VERSION 5.7 ;
  NOWIREEXTENSIONATPIN ON ;
  DIVIDERCHAR "/" ;
  BUSBITCHARS "[]" ;
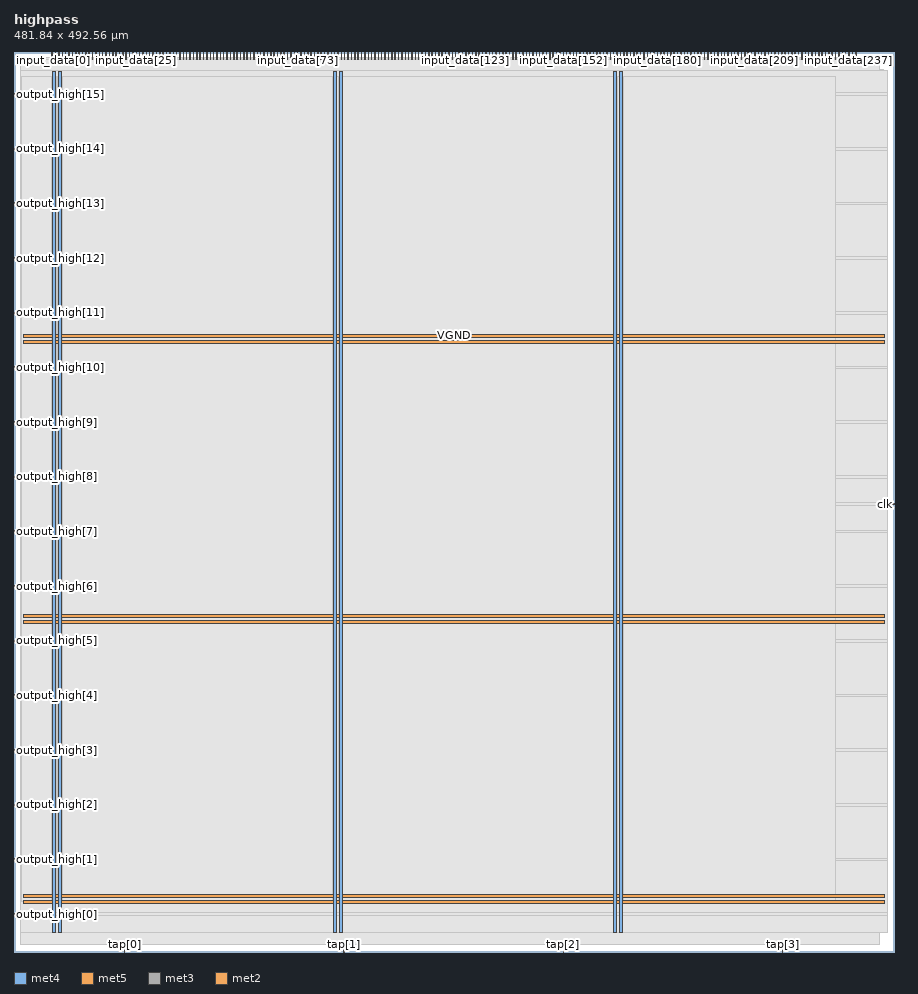
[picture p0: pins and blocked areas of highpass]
MACRO highpass
  CLASS BLOCK ;
  FOREIGN highpass ;
  ORIGIN 0.000 0.000 ;
  SIZE 481.840 BY 492.560 ;
  PIN VGND
    DIRECTION INOUT ;
    USE GROUND ;
    PORT
      LAYER met4 ;
        RECT 24.340 10.640 25.940 481.680 ;
    END
    PORT
      LAYER met4 ;
        RECT 177.940 10.640 179.540 481.680 ;
    END
    PORT
      LAYER met4 ;
        RECT 331.540 10.640 333.140 481.680 ;
    END
    PORT
      LAYER met5 ;
        RECT 5.280 30.030 476.340 31.630 ;
    END
    PORT
      LAYER met5 ;
        RECT 5.280 183.210 476.340 184.810 ;
    END
    PORT
      LAYER met5 ;
        RECT 5.280 336.390 476.340 337.990 ;
    END
  END VGND
  PIN VPWR
    DIRECTION INOUT ;
    USE POWER ;
    PORT
      LAYER met4 ;
        RECT 21.040 10.640 22.640 481.680 ;
    END
    PORT
      LAYER met4 ;
        RECT 174.640 10.640 176.240 481.680 ;
    END
    PORT
      LAYER met4 ;
        RECT 328.240 10.640 329.840 481.680 ;
    END
    PORT
      LAYER met5 ;
        RECT 5.280 26.730 476.340 28.330 ;
    END
    PORT
      LAYER met5 ;
        RECT 5.280 179.910 476.340 181.510 ;
    END
    PORT
      LAYER met5 ;
        RECT 5.280 333.090 476.340 334.690 ;
    END
  END VPWR
  PIN clk
    DIRECTION INPUT ;
    USE SIGNAL ;
    ANTENNAGATEAREA 0.852000 ;
    ANTENNADIFFAREA 0.434700 ;
    PORT
      LAYER met3 ;
        RECT 477.840 244.840 481.840 245.440 ;
    END
  END clk
  PIN input_data[0]
    DIRECTION INPUT ;
    USE SIGNAL ;
    ANTENNAGATEAREA 0.159000 ;
    PORT
      LAYER met2 ;
        RECT 20.790 488.560 21.070 492.560 ;
    END
  END input_data[0]
  PIN input_data[100]
    DIRECTION INPUT ;
    USE SIGNAL ;
    ANTENNAGATEAREA 0.196500 ;
    PORT
      LAYER met2 ;
        RECT 204.790 488.560 205.070 492.560 ;
    END
  END input_data[100]
  PIN input_data[101]
    DIRECTION INPUT ;
    USE SIGNAL ;
    ANTENNAGATEAREA 0.159000 ;
    PORT
      LAYER met2 ;
        RECT 206.630 488.560 206.910 492.560 ;
    END
  END input_data[101]
  PIN input_data[102]
    DIRECTION INPUT ;
    USE SIGNAL ;
    ANTENNAGATEAREA 0.196500 ;
    PORT
      LAYER met2 ;
        RECT 208.470 488.560 208.750 492.560 ;
    END
  END input_data[102]
  PIN input_data[103]
    DIRECTION INPUT ;
    USE SIGNAL ;
    ANTENNAGATEAREA 0.196500 ;
    PORT
      LAYER met2 ;
        RECT 210.310 488.560 210.590 492.560 ;
    END
  END input_data[103]
  PIN input_data[104]
    DIRECTION INPUT ;
    USE SIGNAL ;
    ANTENNAGATEAREA 0.196500 ;
    PORT
      LAYER met2 ;
        RECT 212.150 488.560 212.430 492.560 ;
    END
  END input_data[104]
  PIN input_data[105]
    DIRECTION INPUT ;
    USE SIGNAL ;
    ANTENNAGATEAREA 0.196500 ;
    PORT
      LAYER met2 ;
        RECT 213.990 488.560 214.270 492.560 ;
    END
  END input_data[105]
  PIN input_data[106]
    DIRECTION INPUT ;
    USE SIGNAL ;
    ANTENNAGATEAREA 0.196500 ;
    PORT
      LAYER met2 ;
        RECT 215.830 488.560 216.110 492.560 ;
    END
  END input_data[106]
  PIN input_data[107]
    DIRECTION INPUT ;
    USE SIGNAL ;
    ANTENNAGATEAREA 0.196500 ;
    PORT
      LAYER met2 ;
        RECT 217.670 488.560 217.950 492.560 ;
    END
  END input_data[107]
  PIN input_data[108]
    DIRECTION INPUT ;
    USE SIGNAL ;
    ANTENNAGATEAREA 0.159000 ;
    PORT
      LAYER met2 ;
        RECT 219.510 488.560 219.790 492.560 ;
    END
  END input_data[108]
  PIN input_data[109]
    DIRECTION INPUT ;
    USE SIGNAL ;
    ANTENNAGATEAREA 0.196500 ;
    PORT
      LAYER met2 ;
        RECT 221.350 488.560 221.630 492.560 ;
    END
  END input_data[109]
  PIN input_data[10]
    DIRECTION INPUT ;
    USE SIGNAL ;
    ANTENNAGATEAREA 0.247500 ;
    PORT
      LAYER met2 ;
        RECT 39.190 488.560 39.470 492.560 ;
    END
  END input_data[10]
  PIN input_data[110]
    DIRECTION INPUT ;
    USE SIGNAL ;
    ANTENNAGATEAREA 0.196500 ;
    PORT
      LAYER met2 ;
        RECT 223.190 488.560 223.470 492.560 ;
    END
  END input_data[110]
  PIN input_data[111]
    DIRECTION INPUT ;
    USE SIGNAL ;
    ANTENNAGATEAREA 0.196500 ;
    PORT
      LAYER met2 ;
        RECT 225.030 488.560 225.310 492.560 ;
    END
  END input_data[111]
  PIN input_data[112]
    DIRECTION INPUT ;
    USE SIGNAL ;
    ANTENNAGATEAREA 0.213000 ;
    PORT
      LAYER met2 ;
        RECT 226.870 488.560 227.150 492.560 ;
    END
  END input_data[112]
  PIN input_data[113]
    DIRECTION INPUT ;
    USE SIGNAL ;
    ANTENNAGATEAREA 0.159000 ;
    PORT
      LAYER met2 ;
        RECT 228.710 488.560 228.990 492.560 ;
    END
  END input_data[113]
  PIN input_data[114]
    DIRECTION INPUT ;
    USE SIGNAL ;
    ANTENNAGATEAREA 0.196500 ;
    PORT
      LAYER met2 ;
        RECT 230.550 488.560 230.830 492.560 ;
    END
  END input_data[114]
  PIN input_data[115]
    DIRECTION INPUT ;
    USE SIGNAL ;
    ANTENNAGATEAREA 0.213000 ;
    PORT
      LAYER met2 ;
        RECT 232.390 488.560 232.670 492.560 ;
    END
  END input_data[115]
  PIN input_data[116]
    DIRECTION INPUT ;
    USE SIGNAL ;
    ANTENNAGATEAREA 0.213000 ;
    PORT
      LAYER met2 ;
        RECT 234.230 488.560 234.510 492.560 ;
    END
  END input_data[116]
  PIN input_data[117]
    DIRECTION INPUT ;
    USE SIGNAL ;
    ANTENNAGATEAREA 0.126000 ;
    PORT
      LAYER met2 ;
        RECT 236.070 488.560 236.350 492.560 ;
    END
  END input_data[117]
  PIN input_data[118]
    DIRECTION INPUT ;
    USE SIGNAL ;
    ANTENNAGATEAREA 0.196500 ;
    PORT
      LAYER met2 ;
        RECT 237.910 488.560 238.190 492.560 ;
    END
  END input_data[118]
  PIN input_data[119]
    DIRECTION INPUT ;
    USE SIGNAL ;
    ANTENNAGATEAREA 0.196500 ;
    PORT
      LAYER met2 ;
        RECT 239.750 488.560 240.030 492.560 ;
    END
  END input_data[119]
  PIN input_data[11]
    DIRECTION INPUT ;
    USE SIGNAL ;
    ANTENNAGATEAREA 0.159000 ;
    PORT
      LAYER met2 ;
        RECT 41.030 488.560 41.310 492.560 ;
    END
  END input_data[11]
  PIN input_data[120]
    DIRECTION INPUT ;
    USE SIGNAL ;
    ANTENNAGATEAREA 0.196500 ;
    PORT
      LAYER met2 ;
        RECT 241.590 488.560 241.870 492.560 ;
    END
  END input_data[120]
  PIN input_data[121]
    DIRECTION INPUT ;
    USE SIGNAL ;
    ANTENNAGATEAREA 0.196500 ;
    PORT
      LAYER met2 ;
        RECT 243.430 488.560 243.710 492.560 ;
    END
  END input_data[121]
  PIN input_data[122]
    DIRECTION INPUT ;
    USE SIGNAL ;
    ANTENNAGATEAREA 0.159000 ;
    PORT
      LAYER met2 ;
        RECT 245.270 488.560 245.550 492.560 ;
    END
  END input_data[122]
  PIN input_data[123]
    DIRECTION INPUT ;
    USE SIGNAL ;
    ANTENNAGATEAREA 0.159000 ;
    PORT
      LAYER met2 ;
        RECT 247.110 488.560 247.390 492.560 ;
    END
  END input_data[123]
  PIN input_data[124]
    DIRECTION INPUT ;
    USE SIGNAL ;
    ANTENNAGATEAREA 0.159000 ;
    PORT
      LAYER met2 ;
        RECT 248.950 488.560 249.230 492.560 ;
    END
  END input_data[124]
  PIN input_data[125]
    DIRECTION INPUT ;
    USE SIGNAL ;
    ANTENNAGATEAREA 0.196500 ;
    PORT
      LAYER met2 ;
        RECT 250.790 488.560 251.070 492.560 ;
    END
  END input_data[125]
  PIN input_data[126]
    DIRECTION INPUT ;
    USE SIGNAL ;
    ANTENNAGATEAREA 0.196500 ;
    PORT
      LAYER met2 ;
        RECT 252.630 488.560 252.910 492.560 ;
    END
  END input_data[126]
  PIN input_data[127]
    DIRECTION INPUT ;
    USE SIGNAL ;
    PORT
      LAYER met2 ;
        RECT 254.470 488.560 254.750 492.560 ;
    END
  END input_data[127]
  PIN input_data[128]
    DIRECTION INPUT ;
    USE SIGNAL ;
    ANTENNAGATEAREA 0.247500 ;
    PORT
      LAYER met2 ;
        RECT 256.310 488.560 256.590 492.560 ;
    END
  END input_data[128]
  PIN input_data[129]
    DIRECTION INPUT ;
    USE SIGNAL ;
    ANTENNAGATEAREA 0.213000 ;
    PORT
      LAYER met2 ;
        RECT 258.150 488.560 258.430 492.560 ;
    END
  END input_data[129]
  PIN input_data[12]
    DIRECTION INPUT ;
    USE SIGNAL ;
    ANTENNAGATEAREA 0.495000 ;
    PORT
      LAYER met2 ;
        RECT 42.870 488.560 43.150 492.560 ;
    END
  END input_data[12]
  PIN input_data[130]
    DIRECTION INPUT ;
    USE SIGNAL ;
    ANTENNAGATEAREA 0.213000 ;
    PORT
      LAYER met2 ;
        RECT 259.990 488.560 260.270 492.560 ;
    END
  END input_data[130]
  PIN input_data[131]
    DIRECTION INPUT ;
    USE SIGNAL ;
    ANTENNAGATEAREA 0.213000 ;
    PORT
      LAYER met2 ;
        RECT 261.830 488.560 262.110 492.560 ;
    END
  END input_data[131]
  PIN input_data[132]
    DIRECTION INPUT ;
    USE SIGNAL ;
    ANTENNAGATEAREA 0.213000 ;
    PORT
      LAYER met2 ;
        RECT 263.670 488.560 263.950 492.560 ;
    END
  END input_data[132]
  PIN input_data[133]
    DIRECTION INPUT ;
    USE SIGNAL ;
    ANTENNAGATEAREA 0.213000 ;
    PORT
      LAYER met2 ;
        RECT 265.510 488.560 265.790 492.560 ;
    END
  END input_data[133]
  PIN input_data[134]
    DIRECTION INPUT ;
    USE SIGNAL ;
    ANTENNAGATEAREA 0.213000 ;
    PORT
      LAYER met2 ;
        RECT 267.350 488.560 267.630 492.560 ;
    END
  END input_data[134]
  PIN input_data[135]
    DIRECTION INPUT ;
    USE SIGNAL ;
    ANTENNAGATEAREA 0.213000 ;
    PORT
      LAYER met2 ;
        RECT 269.190 488.560 269.470 492.560 ;
    END
  END input_data[135]
  PIN input_data[136]
    DIRECTION INPUT ;
    USE SIGNAL ;
    ANTENNAGATEAREA 0.495000 ;
    PORT
      LAYER met2 ;
        RECT 271.030 488.560 271.310 492.560 ;
    END
  END input_data[136]
  PIN input_data[137]
    DIRECTION INPUT ;
    USE SIGNAL ;
    ANTENNAGATEAREA 0.426000 ;
    PORT
      LAYER met2 ;
        RECT 272.870 488.560 273.150 492.560 ;
    END
  END input_data[137]
  PIN input_data[138]
    DIRECTION INPUT ;
    USE SIGNAL ;
    ANTENNAGATEAREA 0.213000 ;
    PORT
      LAYER met2 ;
        RECT 274.710 488.560 274.990 492.560 ;
    END
  END input_data[138]
  PIN input_data[139]
    DIRECTION INPUT ;
    USE SIGNAL ;
    ANTENNAGATEAREA 0.247500 ;
    PORT
      LAYER met2 ;
        RECT 276.550 488.560 276.830 492.560 ;
    END
  END input_data[139]
  PIN input_data[13]
    DIRECTION INPUT ;
    USE SIGNAL ;
    ANTENNAGATEAREA 0.495000 ;
    PORT
      LAYER met2 ;
        RECT 44.710 488.560 44.990 492.560 ;
    END
  END input_data[13]
  PIN input_data[140]
    DIRECTION INPUT ;
    USE SIGNAL ;
    ANTENNAGATEAREA 0.247500 ;
    PORT
      LAYER met2 ;
        RECT 278.390 488.560 278.670 492.560 ;
    END
  END input_data[140]
  PIN input_data[141]
    DIRECTION INPUT ;
    USE SIGNAL ;
    ANTENNAGATEAREA 0.247500 ;
    PORT
      LAYER met2 ;
        RECT 280.230 488.560 280.510 492.560 ;
    END
  END input_data[141]
  PIN input_data[142]
    DIRECTION INPUT ;
    USE SIGNAL ;
    ANTENNAGATEAREA 0.196500 ;
    PORT
      LAYER met2 ;
        RECT 282.070 488.560 282.350 492.560 ;
    END
  END input_data[142]
  PIN input_data[143]
    DIRECTION INPUT ;
    USE SIGNAL ;
    ANTENNAGATEAREA 0.126000 ;
    PORT
      LAYER met2 ;
        RECT 283.910 488.560 284.190 492.560 ;
    END
  END input_data[143]
  PIN input_data[144]
    DIRECTION INPUT ;
    USE SIGNAL ;
    ANTENNAGATEAREA 0.213000 ;
    PORT
      LAYER met2 ;
        RECT 285.750 488.560 286.030 492.560 ;
    END
  END input_data[144]
  PIN input_data[145]
    DIRECTION INPUT ;
    USE SIGNAL ;
    ANTENNAGATEAREA 0.126000 ;
    PORT
      LAYER met2 ;
        RECT 287.590 488.560 287.870 492.560 ;
    END
  END input_data[145]
  PIN input_data[146]
    DIRECTION INPUT ;
    USE SIGNAL ;
    ANTENNAGATEAREA 0.213000 ;
    PORT
      LAYER met2 ;
        RECT 289.430 488.560 289.710 492.560 ;
    END
  END input_data[146]
  PIN input_data[147]
    DIRECTION INPUT ;
    USE SIGNAL ;
    ANTENNAGATEAREA 0.159000 ;
    PORT
      LAYER met2 ;
        RECT 291.270 488.560 291.550 492.560 ;
    END
  END input_data[147]
  PIN input_data[148]
    DIRECTION INPUT ;
    USE SIGNAL ;
    ANTENNAGATEAREA 0.126000 ;
    PORT
      LAYER met2 ;
        RECT 293.110 488.560 293.390 492.560 ;
    END
  END input_data[148]
  PIN input_data[149]
    DIRECTION INPUT ;
    USE SIGNAL ;
    ANTENNAGATEAREA 0.213000 ;
    PORT
      LAYER met2 ;
        RECT 294.950 488.560 295.230 492.560 ;
    END
  END input_data[149]
  PIN input_data[14]
    DIRECTION INPUT ;
    USE SIGNAL ;
    ANTENNAGATEAREA 0.159000 ;
    PORT
      LAYER met2 ;
        RECT 46.550 488.560 46.830 492.560 ;
    END
  END input_data[14]
  PIN input_data[150]
    DIRECTION INPUT ;
    USE SIGNAL ;
    ANTENNAGATEAREA 0.213000 ;
    PORT
      LAYER met2 ;
        RECT 296.790 488.560 297.070 492.560 ;
    END
  END input_data[150]
  PIN input_data[151]
    DIRECTION INPUT ;
    USE SIGNAL ;
    ANTENNAGATEAREA 0.159000 ;
    PORT
      LAYER met2 ;
        RECT 298.630 488.560 298.910 492.560 ;
    END
  END input_data[151]
  PIN input_data[152]
    DIRECTION INPUT ;
    USE SIGNAL ;
    ANTENNAGATEAREA 0.213000 ;
    PORT
      LAYER met2 ;
        RECT 300.470 488.560 300.750 492.560 ;
    END
  END input_data[152]
  PIN input_data[153]
    DIRECTION INPUT ;
    USE SIGNAL ;
    ANTENNAGATEAREA 0.213000 ;
    PORT
      LAYER met2 ;
        RECT 302.310 488.560 302.590 492.560 ;
    END
  END input_data[153]
  PIN input_data[154]
    DIRECTION INPUT ;
    USE SIGNAL ;
    ANTENNAGATEAREA 0.213000 ;
    PORT
      LAYER met2 ;
        RECT 304.150 488.560 304.430 492.560 ;
    END
  END input_data[154]
  PIN input_data[155]
    DIRECTION INPUT ;
    USE SIGNAL ;
    ANTENNAGATEAREA 0.196500 ;
    PORT
      LAYER met2 ;
        RECT 305.990 488.560 306.270 492.560 ;
    END
  END input_data[155]
  PIN input_data[156]
    DIRECTION INPUT ;
    USE SIGNAL ;
    ANTENNAGATEAREA 0.213000 ;
    PORT
      LAYER met2 ;
        RECT 307.830 488.560 308.110 492.560 ;
    END
  END input_data[156]
  PIN input_data[157]
    DIRECTION INPUT ;
    USE SIGNAL ;
    ANTENNAGATEAREA 0.213000 ;
    PORT
      LAYER met2 ;
        RECT 309.670 488.560 309.950 492.560 ;
    END
  END input_data[157]
  PIN input_data[158]
    DIRECTION INPUT ;
    USE SIGNAL ;
    ANTENNAGATEAREA 0.196500 ;
    PORT
      LAYER met2 ;
        RECT 311.510 488.560 311.790 492.560 ;
    END
  END input_data[158]
  PIN input_data[159]
    DIRECTION INPUT ;
    USE SIGNAL ;
    ANTENNAGATEAREA 0.196500 ;
    PORT
      LAYER met2 ;
        RECT 313.350 488.560 313.630 492.560 ;
    END
  END input_data[159]
  PIN input_data[15]
    DIRECTION INPUT ;
    USE SIGNAL ;
    ANTENNAGATEAREA 0.213000 ;
    PORT
      LAYER met2 ;
        RECT 48.390 488.560 48.670 492.560 ;
    END
  END input_data[15]
  PIN input_data[160]
    DIRECTION INPUT ;
    USE SIGNAL ;
    ANTENNAGATEAREA 0.426000 ;
    PORT
      LAYER met2 ;
        RECT 315.190 488.560 315.470 492.560 ;
    END
  END input_data[160]
  PIN input_data[161]
    DIRECTION INPUT ;
    USE SIGNAL ;
    ANTENNAGATEAREA 0.247500 ;
    PORT
      LAYER met2 ;
        RECT 317.030 488.560 317.310 492.560 ;
    END
  END input_data[161]
  PIN input_data[162]
    DIRECTION INPUT ;
    USE SIGNAL ;
    ANTENNAGATEAREA 0.247500 ;
    PORT
      LAYER met2 ;
        RECT 318.870 488.560 319.150 492.560 ;
    END
  END input_data[162]
  PIN input_data[163]
    DIRECTION INPUT ;
    USE SIGNAL ;
    ANTENNAGATEAREA 0.247500 ;
    PORT
      LAYER met2 ;
        RECT 320.710 488.560 320.990 492.560 ;
    END
  END input_data[163]
  PIN input_data[164]
    DIRECTION INPUT ;
    USE SIGNAL ;
    ANTENNAGATEAREA 0.126000 ;
    PORT
      LAYER met2 ;
        RECT 322.550 488.560 322.830 492.560 ;
    END
  END input_data[164]
  PIN input_data[165]
    DIRECTION INPUT ;
    USE SIGNAL ;
    ANTENNAGATEAREA 0.213000 ;
    PORT
      LAYER met2 ;
        RECT 324.390 488.560 324.670 492.560 ;
    END
  END input_data[165]
  PIN input_data[166]
    DIRECTION INPUT ;
    USE SIGNAL ;
    ANTENNAGATEAREA 0.196500 ;
    PORT
      LAYER met2 ;
        RECT 326.230 488.560 326.510 492.560 ;
    END
  END input_data[166]
  PIN input_data[167]
    DIRECTION INPUT ;
    USE SIGNAL ;
    ANTENNAGATEAREA 0.213000 ;
    PORT
      LAYER met2 ;
        RECT 328.070 488.560 328.350 492.560 ;
    END
  END input_data[167]
  PIN input_data[168]
    DIRECTION INPUT ;
    USE SIGNAL ;
    ANTENNAGATEAREA 0.196500 ;
    PORT
      LAYER met2 ;
        RECT 329.910 488.560 330.190 492.560 ;
    END
  END input_data[168]
  PIN input_data[169]
    DIRECTION INPUT ;
    USE SIGNAL ;
    ANTENNAGATEAREA 0.196500 ;
    PORT
      LAYER met2 ;
        RECT 331.750 488.560 332.030 492.560 ;
    END
  END input_data[169]
  PIN input_data[16]
    DIRECTION INPUT ;
    USE SIGNAL ;
    ANTENNAGATEAREA 0.247500 ;
    PORT
      LAYER met2 ;
        RECT 50.230 488.560 50.510 492.560 ;
    END
  END input_data[16]
  PIN input_data[170]
    DIRECTION INPUT ;
    USE SIGNAL ;
    ANTENNAGATEAREA 0.196500 ;
    PORT
      LAYER met2 ;
        RECT 333.590 488.560 333.870 492.560 ;
    END
  END input_data[170]
  PIN input_data[171]
    DIRECTION INPUT ;
    USE SIGNAL ;
    ANTENNAGATEAREA 0.213000 ;
    PORT
      LAYER met2 ;
        RECT 335.430 488.560 335.710 492.560 ;
    END
  END input_data[171]
  PIN input_data[172]
    DIRECTION INPUT ;
    USE SIGNAL ;
    ANTENNAGATEAREA 0.159000 ;
    PORT
      LAYER met2 ;
        RECT 337.270 488.560 337.550 492.560 ;
    END
  END input_data[172]
  PIN input_data[173]
    DIRECTION INPUT ;
    USE SIGNAL ;
    ANTENNAGATEAREA 0.213000 ;
    PORT
      LAYER met2 ;
        RECT 339.110 488.560 339.390 492.560 ;
    END
  END input_data[173]
  PIN input_data[174]
    DIRECTION INPUT ;
    USE SIGNAL ;
    ANTENNAGATEAREA 0.196500 ;
    PORT
      LAYER met2 ;
        RECT 340.950 488.560 341.230 492.560 ;
    END
  END input_data[174]
  PIN input_data[175]
    DIRECTION INPUT ;
    USE SIGNAL ;
    ANTENNAGATEAREA 0.196500 ;
    PORT
      LAYER met2 ;
        RECT 342.790 488.560 343.070 492.560 ;
    END
  END input_data[175]
  PIN input_data[176]
    DIRECTION INPUT ;
    USE SIGNAL ;
    ANTENNAGATEAREA 0.213000 ;
    PORT
      LAYER met2 ;
        RECT 344.630 488.560 344.910 492.560 ;
    END
  END input_data[176]
  PIN input_data[177]
    DIRECTION INPUT ;
    USE SIGNAL ;
    ANTENNAGATEAREA 0.247500 ;
    PORT
      LAYER met2 ;
        RECT 346.470 488.560 346.750 492.560 ;
    END
  END input_data[177]
  PIN input_data[178]
    DIRECTION INPUT ;
    USE SIGNAL ;
    ANTENNAGATEAREA 0.247500 ;
    PORT
      LAYER met2 ;
        RECT 348.310 488.560 348.590 492.560 ;
    END
  END input_data[178]
  PIN input_data[179]
    DIRECTION INPUT ;
    USE SIGNAL ;
    ANTENNAGATEAREA 0.247500 ;
    PORT
      LAYER met2 ;
        RECT 350.150 488.560 350.430 492.560 ;
    END
  END input_data[179]
  PIN input_data[17]
    DIRECTION INPUT ;
    USE SIGNAL ;
    ANTENNAGATEAREA 0.213000 ;
    PORT
      LAYER met2 ;
        RECT 52.070 488.560 52.350 492.560 ;
    END
  END input_data[17]
  PIN input_data[180]
    DIRECTION INPUT ;
    USE SIGNAL ;
    ANTENNAGATEAREA 0.213000 ;
    PORT
      LAYER met2 ;
        RECT 351.990 488.560 352.270 492.560 ;
    END
  END input_data[180]
  PIN input_data[181]
    DIRECTION INPUT ;
    USE SIGNAL ;
    ANTENNAGATEAREA 0.159000 ;
    PORT
      LAYER met2 ;
        RECT 353.830 488.560 354.110 492.560 ;
    END
  END input_data[181]
  PIN input_data[182]
    DIRECTION INPUT ;
    USE SIGNAL ;
    ANTENNAGATEAREA 0.159000 ;
    PORT
      LAYER met2 ;
        RECT 355.670 488.560 355.950 492.560 ;
    END
  END input_data[182]
  PIN input_data[183]
    DIRECTION INPUT ;
    USE SIGNAL ;
    ANTENNAGATEAREA 0.159000 ;
    PORT
      LAYER met2 ;
        RECT 357.510 488.560 357.790 492.560 ;
    END
  END input_data[183]
  PIN input_data[184]
    DIRECTION INPUT ;
    USE SIGNAL ;
    ANTENNAGATEAREA 0.159000 ;
    PORT
      LAYER met2 ;
        RECT 359.350 488.560 359.630 492.560 ;
    END
  END input_data[184]
  PIN input_data[185]
    DIRECTION INPUT ;
    USE SIGNAL ;
    ANTENNAGATEAREA 0.213000 ;
    PORT
      LAYER met2 ;
        RECT 361.190 488.560 361.470 492.560 ;
    END
  END input_data[185]
  PIN input_data[186]
    DIRECTION INPUT ;
    USE SIGNAL ;
    ANTENNAGATEAREA 0.213000 ;
    PORT
      LAYER met2 ;
        RECT 363.030 488.560 363.310 492.560 ;
    END
  END input_data[186]
  PIN input_data[187]
    DIRECTION INPUT ;
    USE SIGNAL ;
    ANTENNAGATEAREA 0.213000 ;
    PORT
      LAYER met2 ;
        RECT 364.870 488.560 365.150 492.560 ;
    END
  END input_data[187]
  PIN input_data[188]
    DIRECTION INPUT ;
    USE SIGNAL ;
    ANTENNAGATEAREA 0.159000 ;
    PORT
      LAYER met2 ;
        RECT 366.710 488.560 366.990 492.560 ;
    END
  END input_data[188]
  PIN input_data[189]
    DIRECTION INPUT ;
    USE SIGNAL ;
    ANTENNAGATEAREA 0.196500 ;
    PORT
      LAYER met2 ;
        RECT 368.550 488.560 368.830 492.560 ;
    END
  END input_data[189]
  PIN input_data[18]
    DIRECTION INPUT ;
    USE SIGNAL ;
    ANTENNAGATEAREA 0.247500 ;
    PORT
      LAYER met2 ;
        RECT 53.910 488.560 54.190 492.560 ;
    END
  END input_data[18]
  PIN input_data[190]
    DIRECTION INPUT ;
    USE SIGNAL ;
    ANTENNAGATEAREA 0.196500 ;
    PORT
      LAYER met2 ;
        RECT 370.390 488.560 370.670 492.560 ;
    END
  END input_data[190]
  PIN input_data[191]
    DIRECTION INPUT ;
    USE SIGNAL ;
    PORT
      LAYER met2 ;
        RECT 372.230 488.560 372.510 492.560 ;
    END
  END input_data[191]
  PIN input_data[192]
    DIRECTION INPUT ;
    USE SIGNAL ;
    ANTENNAGATEAREA 0.159000 ;
    PORT
      LAYER met2 ;
        RECT 374.070 488.560 374.350 492.560 ;
    END
  END input_data[192]
  PIN input_data[193]
    DIRECTION INPUT ;
    USE SIGNAL ;
    ANTENNAGATEAREA 0.213000 ;
    PORT
      LAYER met2 ;
        RECT 375.910 488.560 376.190 492.560 ;
    END
  END input_data[193]
  PIN input_data[194]
    DIRECTION INPUT ;
    USE SIGNAL ;
    ANTENNAGATEAREA 0.213000 ;
    PORT
      LAYER met2 ;
        RECT 377.750 488.560 378.030 492.560 ;
    END
  END input_data[194]
  PIN input_data[195]
    DIRECTION INPUT ;
    USE SIGNAL ;
    ANTENNAGATEAREA 0.159000 ;
    PORT
      LAYER met2 ;
        RECT 379.590 488.560 379.870 492.560 ;
    END
  END input_data[195]
  PIN input_data[196]
    DIRECTION INPUT ;
    USE SIGNAL ;
    ANTENNAGATEAREA 0.213000 ;
    PORT
      LAYER met2 ;
        RECT 381.430 488.560 381.710 492.560 ;
    END
  END input_data[196]
  PIN input_data[197]
    DIRECTION INPUT ;
    USE SIGNAL ;
    ANTENNAGATEAREA 0.213000 ;
    PORT
      LAYER met2 ;
        RECT 383.270 488.560 383.550 492.560 ;
    END
  END input_data[197]
  PIN input_data[198]
    DIRECTION INPUT ;
    USE SIGNAL ;
    ANTENNAGATEAREA 0.213000 ;
    PORT
      LAYER met2 ;
        RECT 385.110 488.560 385.390 492.560 ;
    END
  END input_data[198]
  PIN input_data[199]
    DIRECTION INPUT ;
    USE SIGNAL ;
    ANTENNAGATEAREA 0.213000 ;
    PORT
      LAYER met2 ;
        RECT 386.950 488.560 387.230 492.560 ;
    END
  END input_data[199]
  PIN input_data[19]
    DIRECTION INPUT ;
    USE SIGNAL ;
    ANTENNAGATEAREA 0.159000 ;
    PORT
      LAYER met2 ;
        RECT 55.750 488.560 56.030 492.560 ;
    END
  END input_data[19]
  PIN input_data[1]
    DIRECTION INPUT ;
    USE SIGNAL ;
    ANTENNAGATEAREA 0.159000 ;
    PORT
      LAYER met2 ;
        RECT 22.630 488.560 22.910 492.560 ;
    END
  END input_data[1]
  PIN input_data[200]
    DIRECTION INPUT ;
    USE SIGNAL ;
    ANTENNAGATEAREA 0.213000 ;
    PORT
      LAYER met2 ;
        RECT 388.790 488.560 389.070 492.560 ;
    END
  END input_data[200]
  PIN input_data[201]
    DIRECTION INPUT ;
    USE SIGNAL ;
    ANTENNAGATEAREA 0.126000 ;
    PORT
      LAYER met2 ;
        RECT 390.630 488.560 390.910 492.560 ;
    END
  END input_data[201]
  PIN input_data[202]
    DIRECTION INPUT ;
    USE SIGNAL ;
    ANTENNAGATEAREA 0.126000 ;
    PORT
      LAYER met2 ;
        RECT 392.470 488.560 392.750 492.560 ;
    END
  END input_data[202]
  PIN input_data[203]
    DIRECTION INPUT ;
    USE SIGNAL ;
    ANTENNAGATEAREA 0.126000 ;
    PORT
      LAYER met2 ;
        RECT 394.310 488.560 394.590 492.560 ;
    END
  END input_data[203]
  PIN input_data[204]
    DIRECTION INPUT ;
    USE SIGNAL ;
    ANTENNAGATEAREA 0.196500 ;
    PORT
      LAYER met2 ;
        RECT 396.150 488.560 396.430 492.560 ;
    END
  END input_data[204]
  PIN input_data[205]
    DIRECTION INPUT ;
    USE SIGNAL ;
    ANTENNAGATEAREA 0.196500 ;
    PORT
      LAYER met2 ;
        RECT 397.990 488.560 398.270 492.560 ;
    END
  END input_data[205]
  PIN input_data[206]
    DIRECTION INPUT ;
    USE SIGNAL ;
    ANTENNAGATEAREA 0.196500 ;
    PORT
      LAYER met2 ;
        RECT 399.830 488.560 400.110 492.560 ;
    END
  END input_data[206]
  PIN input_data[207]
    DIRECTION INPUT ;
    USE SIGNAL ;
    PORT
      LAYER met2 ;
        RECT 401.670 488.560 401.950 492.560 ;
    END
  END input_data[207]
  PIN input_data[208]
    DIRECTION INPUT ;
    USE SIGNAL ;
    PORT
      LAYER met2 ;
        RECT 403.510 488.560 403.790 492.560 ;
    END
  END input_data[208]
  PIN input_data[209]
    DIRECTION INPUT ;
    USE SIGNAL ;
    PORT
      LAYER met2 ;
        RECT 405.350 488.560 405.630 492.560 ;
    END
  END input_data[209]
  PIN input_data[20]
    DIRECTION INPUT ;
    USE SIGNAL ;
    ANTENNAGATEAREA 0.247500 ;
    PORT
      LAYER met2 ;
        RECT 57.590 488.560 57.870 492.560 ;
    END
  END input_data[20]
  PIN input_data[210]
    DIRECTION INPUT ;
    USE SIGNAL ;
    PORT
      LAYER met2 ;
        RECT 407.190 488.560 407.470 492.560 ;
    END
  END input_data[210]
  PIN input_data[211]
    DIRECTION INPUT ;
    USE SIGNAL ;
    PORT
      LAYER met2 ;
        RECT 409.030 488.560 409.310 492.560 ;
    END
  END input_data[211]
  PIN input_data[212]
    DIRECTION INPUT ;
    USE SIGNAL ;
    PORT
      LAYER met2 ;
        RECT 410.870 488.560 411.150 492.560 ;
    END
  END input_data[212]
  PIN input_data[213]
    DIRECTION INPUT ;
    USE SIGNAL ;
    PORT
      LAYER met2 ;
        RECT 412.710 488.560 412.990 492.560 ;
    END
  END input_data[213]
  PIN input_data[214]
    DIRECTION INPUT ;
    USE SIGNAL ;
    PORT
      LAYER met2 ;
        RECT 414.550 488.560 414.830 492.560 ;
    END
  END input_data[214]
  PIN input_data[215]
    DIRECTION INPUT ;
    USE SIGNAL ;
    PORT
      LAYER met2 ;
        RECT 416.390 488.560 416.670 492.560 ;
    END
  END input_data[215]
  PIN input_data[216]
    DIRECTION INPUT ;
    USE SIGNAL ;
    PORT
      LAYER met2 ;
        RECT 418.230 488.560 418.510 492.560 ;
    END
  END input_data[216]
  PIN input_data[217]
    DIRECTION INPUT ;
    USE SIGNAL ;
    PORT
      LAYER met2 ;
        RECT 420.070 488.560 420.350 492.560 ;
    END
  END input_data[217]
  PIN input_data[218]
    DIRECTION INPUT ;
    USE SIGNAL ;
    PORT
      LAYER met2 ;
        RECT 421.910 488.560 422.190 492.560 ;
    END
  END input_data[218]
  PIN input_data[219]
    DIRECTION INPUT ;
    USE SIGNAL ;
    PORT
      LAYER met2 ;
        RECT 423.750 488.560 424.030 492.560 ;
    END
  END input_data[219]
  PIN input_data[21]
    DIRECTION INPUT ;
    USE SIGNAL ;
    ANTENNAGATEAREA 0.247500 ;
    PORT
      LAYER met2 ;
        RECT 59.430 488.560 59.710 492.560 ;
    END
  END input_data[21]
  PIN input_data[220]
    DIRECTION INPUT ;
    USE SIGNAL ;
    PORT
      LAYER met2 ;
        RECT 425.590 488.560 425.870 492.560 ;
    END
  END input_data[220]
  PIN input_data[221]
    DIRECTION INPUT ;
    USE SIGNAL ;
    PORT
      LAYER met2 ;
        RECT 427.430 488.560 427.710 492.560 ;
    END
  END input_data[221]
  PIN input_data[222]
    DIRECTION INPUT ;
    USE SIGNAL ;
    PORT
      LAYER met2 ;
        RECT 429.270 488.560 429.550 492.560 ;
    END
  END input_data[222]
  PIN input_data[223]
    DIRECTION INPUT ;
    USE SIGNAL ;
    PORT
      LAYER met2 ;
        RECT 431.110 488.560 431.390 492.560 ;
    END
  END input_data[223]
  PIN input_data[224]
    DIRECTION INPUT ;
    USE SIGNAL ;
    ANTENNAGATEAREA 0.159000 ;
    PORT
      LAYER met2 ;
        RECT 432.950 488.560 433.230 492.560 ;
    END
  END input_data[224]
  PIN input_data[225]
    DIRECTION INPUT ;
    USE SIGNAL ;
    ANTENNAGATEAREA 0.247500 ;
    PORT
      LAYER met2 ;
        RECT 434.790 488.560 435.070 492.560 ;
    END
  END input_data[225]
  PIN input_data[226]
    DIRECTION INPUT ;
    USE SIGNAL ;
    ANTENNAGATEAREA 0.213000 ;
    PORT
      LAYER met2 ;
        RECT 436.630 488.560 436.910 492.560 ;
    END
  END input_data[226]
  PIN input_data[227]
    DIRECTION INPUT ;
    USE SIGNAL ;
    ANTENNAGATEAREA 0.213000 ;
    PORT
      LAYER met2 ;
        RECT 438.470 488.560 438.750 492.560 ;
    END
  END input_data[227]
  PIN input_data[228]
    DIRECTION INPUT ;
    USE SIGNAL ;
    ANTENNAGATEAREA 0.159000 ;
    PORT
      LAYER met2 ;
        RECT 440.310 488.560 440.590 492.560 ;
    END
  END input_data[228]
  PIN input_data[229]
    DIRECTION INPUT ;
    USE SIGNAL ;
    ANTENNAGATEAREA 0.213000 ;
    PORT
      LAYER met2 ;
        RECT 442.150 488.560 442.430 492.560 ;
    END
  END input_data[229]
  PIN input_data[22]
    DIRECTION INPUT ;
    USE SIGNAL ;
    ANTENNAGATEAREA 0.247500 ;
    PORT
      LAYER met2 ;
        RECT 61.270 488.560 61.550 492.560 ;
    END
  END input_data[22]
  PIN input_data[230]
    DIRECTION INPUT ;
    USE SIGNAL ;
    ANTENNAGATEAREA 0.213000 ;
    PORT
      LAYER met2 ;
        RECT 443.990 488.560 444.270 492.560 ;
    END
  END input_data[230]
  PIN input_data[231]
    DIRECTION INPUT ;
    USE SIGNAL ;
    ANTENNAGATEAREA 0.213000 ;
    PORT
      LAYER met2 ;
        RECT 445.830 488.560 446.110 492.560 ;
    END
  END input_data[231]
  PIN input_data[232]
    DIRECTION INPUT ;
    USE SIGNAL ;
    ANTENNAGATEAREA 0.213000 ;
    PORT
      LAYER met2 ;
        RECT 447.670 488.560 447.950 492.560 ;
    END
  END input_data[232]
  PIN input_data[233]
    DIRECTION INPUT ;
    USE SIGNAL ;
    ANTENNAGATEAREA 0.126000 ;
    PORT
      LAYER met2 ;
        RECT 449.510 488.560 449.790 492.560 ;
    END
  END input_data[233]
  PIN input_data[234]
    DIRECTION INPUT ;
    USE SIGNAL ;
    ANTENNAGATEAREA 0.126000 ;
    PORT
      LAYER met2 ;
        RECT 451.350 488.560 451.630 492.560 ;
    END
  END input_data[234]
  PIN input_data[235]
    DIRECTION INPUT ;
    USE SIGNAL ;
    ANTENNAGATEAREA 0.196500 ;
    PORT
      LAYER met2 ;
        RECT 453.190 488.560 453.470 492.560 ;
    END
  END input_data[235]
  PIN input_data[236]
    DIRECTION INPUT ;
    USE SIGNAL ;
    ANTENNAGATEAREA 0.196500 ;
    PORT
      LAYER met2 ;
        RECT 455.030 488.560 455.310 492.560 ;
    END
  END input_data[236]
  PIN input_data[237]
    DIRECTION INPUT ;
    USE SIGNAL ;
    ANTENNAGATEAREA 0.196500 ;
    PORT
      LAYER met2 ;
        RECT 456.870 488.560 457.150 492.560 ;
    END
  END input_data[237]
  PIN input_data[238]
    DIRECTION INPUT ;
    USE SIGNAL ;
    PORT
      LAYER met2 ;
        RECT 458.710 488.560 458.990 492.560 ;
    END
  END input_data[238]
  PIN input_data[239]
    DIRECTION INPUT ;
    USE SIGNAL ;
    PORT
      LAYER met2 ;
        RECT 460.550 488.560 460.830 492.560 ;
    END
  END input_data[239]
  PIN input_data[23]
    DIRECTION INPUT ;
    USE SIGNAL ;
    ANTENNAGATEAREA 0.247500 ;
    PORT
      LAYER met2 ;
        RECT 63.110 488.560 63.390 492.560 ;
    END
  END input_data[23]
  PIN input_data[24]
    DIRECTION INPUT ;
    USE SIGNAL ;
    ANTENNAGATEAREA 0.247500 ;
    PORT
      LAYER met2 ;
        RECT 64.950 488.560 65.230 492.560 ;
    END
  END input_data[24]
  PIN input_data[25]
    DIRECTION INPUT ;
    USE SIGNAL ;
    ANTENNAGATEAREA 0.247500 ;
    PORT
      LAYER met2 ;
        RECT 66.790 488.560 67.070 492.560 ;
    END
  END input_data[25]
  PIN input_data[26]
    DIRECTION INPUT ;
    USE SIGNAL ;
    ANTENNAGATEAREA 0.426000 ;
    PORT
      LAYER met2 ;
        RECT 68.630 488.560 68.910 492.560 ;
    END
  END input_data[26]
  PIN input_data[27]
    DIRECTION INPUT ;
    USE SIGNAL ;
    ANTENNAGATEAREA 0.247500 ;
    PORT
      LAYER met2 ;
        RECT 70.470 488.560 70.750 492.560 ;
    END
  END input_data[27]
  PIN input_data[28]
    DIRECTION INPUT ;
    USE SIGNAL ;
    ANTENNAGATEAREA 0.196500 ;
    PORT
      LAYER met2 ;
        RECT 72.310 488.560 72.590 492.560 ;
    END
  END input_data[28]
  PIN input_data[29]
    DIRECTION INPUT ;
    USE SIGNAL ;
    ANTENNAGATEAREA 0.247500 ;
    PORT
      LAYER met2 ;
        RECT 74.150 488.560 74.430 492.560 ;
    END
  END input_data[29]
  PIN input_data[2]
    DIRECTION INPUT ;
    USE SIGNAL ;
    ANTENNAGATEAREA 0.159000 ;
    PORT
      LAYER met2 ;
        RECT 24.470 488.560 24.750 492.560 ;
    END
  END input_data[2]
  PIN input_data[30]
    DIRECTION INPUT ;
    USE SIGNAL ;
    ANTENNAGATEAREA 0.213000 ;
    PORT
      LAYER met2 ;
        RECT 75.990 488.560 76.270 492.560 ;
    END
  END input_data[30]
  PIN input_data[31]
    DIRECTION INPUT ;
    USE SIGNAL ;
    ANTENNAGATEAREA 0.126000 ;
    PORT
      LAYER met2 ;
        RECT 77.830 488.560 78.110 492.560 ;
    END
  END input_data[31]
  PIN input_data[32]
    DIRECTION INPUT ;
    USE SIGNAL ;
    ANTENNAGATEAREA 0.213000 ;
    PORT
      LAYER met2 ;
        RECT 79.670 488.560 79.950 492.560 ;
    END
  END input_data[32]
  PIN input_data[33]
    DIRECTION INPUT ;
    USE SIGNAL ;
    ANTENNAGATEAREA 0.213000 ;
    PORT
      LAYER met2 ;
        RECT 81.510 488.560 81.790 492.560 ;
    END
  END input_data[33]
  PIN input_data[34]
    DIRECTION INPUT ;
    USE SIGNAL ;
    ANTENNAGATEAREA 0.213000 ;
    PORT
      LAYER met2 ;
        RECT 83.350 488.560 83.630 492.560 ;
    END
  END input_data[34]
  PIN input_data[35]
    DIRECTION INPUT ;
    USE SIGNAL ;
    ANTENNAGATEAREA 0.213000 ;
    PORT
      LAYER met2 ;
        RECT 85.190 488.560 85.470 492.560 ;
    END
  END input_data[35]
  PIN input_data[36]
    DIRECTION INPUT ;
    USE SIGNAL ;
    ANTENNAGATEAREA 0.159000 ;
    PORT
      LAYER met2 ;
        RECT 87.030 488.560 87.310 492.560 ;
    END
  END input_data[36]
  PIN input_data[37]
    DIRECTION INPUT ;
    USE SIGNAL ;
    ANTENNAGATEAREA 0.126000 ;
    PORT
      LAYER met2 ;
        RECT 88.870 488.560 89.150 492.560 ;
    END
  END input_data[37]
  PIN input_data[38]
    DIRECTION INPUT ;
    USE SIGNAL ;
    ANTENNAGATEAREA 0.247500 ;
    PORT
      LAYER met2 ;
        RECT 90.710 488.560 90.990 492.560 ;
    END
  END input_data[38]
  PIN input_data[39]
    DIRECTION INPUT ;
    USE SIGNAL ;
    ANTENNAGATEAREA 0.126000 ;
    PORT
      LAYER met2 ;
        RECT 92.550 488.560 92.830 492.560 ;
    END
  END input_data[39]
  PIN input_data[3]
    DIRECTION INPUT ;
    USE SIGNAL ;
    ANTENNAGATEAREA 0.247500 ;
    PORT
      LAYER met2 ;
        RECT 26.310 488.560 26.590 492.560 ;
    END
  END input_data[3]
  PIN input_data[40]
    DIRECTION INPUT ;
    USE SIGNAL ;
    ANTENNAGATEAREA 0.159000 ;
    PORT
      LAYER met2 ;
        RECT 94.390 488.560 94.670 492.560 ;
    END
  END input_data[40]
  PIN input_data[41]
    DIRECTION INPUT ;
    USE SIGNAL ;
    ANTENNAGATEAREA 0.196500 ;
    PORT
      LAYER met2 ;
        RECT 96.230 488.560 96.510 492.560 ;
    END
  END input_data[41]
  PIN input_data[42]
    DIRECTION INPUT ;
    USE SIGNAL ;
    ANTENNAGATEAREA 0.213000 ;
    PORT
      LAYER met2 ;
        RECT 98.070 488.560 98.350 492.560 ;
    END
  END input_data[42]
  PIN input_data[43]
    DIRECTION INPUT ;
    USE SIGNAL ;
    ANTENNAGATEAREA 0.126000 ;
    PORT
      LAYER met2 ;
        RECT 99.910 488.560 100.190 492.560 ;
    END
  END input_data[43]
  PIN input_data[44]
    DIRECTION INPUT ;
    USE SIGNAL ;
    ANTENNAGATEAREA 0.247500 ;
    PORT
      LAYER met2 ;
        RECT 101.750 488.560 102.030 492.560 ;
    END
  END input_data[44]
  PIN input_data[45]
    DIRECTION INPUT ;
    USE SIGNAL ;
    ANTENNAGATEAREA 0.213000 ;
    PORT
      LAYER met2 ;
        RECT 103.590 488.560 103.870 492.560 ;
    END
  END input_data[45]
  PIN input_data[46]
    DIRECTION INPUT ;
    USE SIGNAL ;
    ANTENNAGATEAREA 0.213000 ;
    PORT
      LAYER met2 ;
        RECT 105.430 488.560 105.710 492.560 ;
    END
  END input_data[46]
  PIN input_data[47]
    DIRECTION INPUT ;
    USE SIGNAL ;
    ANTENNAGATEAREA 0.196500 ;
    PORT
      LAYER met2 ;
        RECT 107.270 488.560 107.550 492.560 ;
    END
  END input_data[47]
  PIN input_data[48]
    DIRECTION INPUT ;
    USE SIGNAL ;
    ANTENNAGATEAREA 0.126000 ;
    PORT
      LAYER met2 ;
        RECT 109.110 488.560 109.390 492.560 ;
    END
  END input_data[48]
  PIN input_data[49]
    DIRECTION INPUT ;
    USE SIGNAL ;
    ANTENNAGATEAREA 0.213000 ;
    PORT
      LAYER met2 ;
        RECT 110.950 488.560 111.230 492.560 ;
    END
  END input_data[49]
  PIN input_data[4]
    DIRECTION INPUT ;
    USE SIGNAL ;
    ANTENNAGATEAREA 0.159000 ;
    PORT
      LAYER met2 ;
        RECT 28.150 488.560 28.430 492.560 ;
    END
  END input_data[4]
  PIN input_data[50]
    DIRECTION INPUT ;
    USE SIGNAL ;
    ANTENNAGATEAREA 0.196500 ;
    PORT
      LAYER met2 ;
        RECT 112.790 488.560 113.070 492.560 ;
    END
  END input_data[50]
  PIN input_data[51]
    DIRECTION INPUT ;
    USE SIGNAL ;
    ANTENNAGATEAREA 0.196500 ;
    PORT
      LAYER met2 ;
        RECT 114.630 488.560 114.910 492.560 ;
    END
  END input_data[51]
  PIN input_data[52]
    DIRECTION INPUT ;
    USE SIGNAL ;
    ANTENNAGATEAREA 0.196500 ;
    PORT
      LAYER met2 ;
        RECT 116.470 488.560 116.750 492.560 ;
    END
  END input_data[52]
  PIN input_data[53]
    DIRECTION INPUT ;
    USE SIGNAL ;
    ANTENNAGATEAREA 0.126000 ;
    PORT
      LAYER met2 ;
        RECT 118.310 488.560 118.590 492.560 ;
    END
  END input_data[53]
  PIN input_data[54]
    DIRECTION INPUT ;
    USE SIGNAL ;
    ANTENNAGATEAREA 0.213000 ;
    PORT
      LAYER met2 ;
        RECT 120.150 488.560 120.430 492.560 ;
    END
  END input_data[54]
  PIN input_data[55]
    DIRECTION INPUT ;
    USE SIGNAL ;
    ANTENNAGATEAREA 0.213000 ;
    PORT
      LAYER met2 ;
        RECT 121.990 488.560 122.270 492.560 ;
    END
  END input_data[55]
  PIN input_data[56]
    DIRECTION INPUT ;
    USE SIGNAL ;
    ANTENNAGATEAREA 0.213000 ;
    PORT
      LAYER met2 ;
        RECT 123.830 488.560 124.110 492.560 ;
    END
  END input_data[56]
  PIN input_data[57]
    DIRECTION INPUT ;
    USE SIGNAL ;
    ANTENNAGATEAREA 0.213000 ;
    PORT
      LAYER met2 ;
        RECT 125.670 488.560 125.950 492.560 ;
    END
  END input_data[57]
  PIN input_data[58]
    DIRECTION INPUT ;
    USE SIGNAL ;
    ANTENNAGATEAREA 0.159000 ;
    PORT
      LAYER met2 ;
        RECT 127.510 488.560 127.790 492.560 ;
    END
  END input_data[58]
  PIN input_data[59]
    DIRECTION INPUT ;
    USE SIGNAL ;
    ANTENNAGATEAREA 0.426000 ;
    PORT
      LAYER met2 ;
        RECT 129.350 488.560 129.630 492.560 ;
    END
  END input_data[59]
  PIN input_data[5]
    DIRECTION INPUT ;
    USE SIGNAL ;
    ANTENNAGATEAREA 0.213000 ;
    PORT
      LAYER met2 ;
        RECT 29.990 488.560 30.270 492.560 ;
    END
  END input_data[5]
  PIN input_data[60]
    DIRECTION INPUT ;
    USE SIGNAL ;
    ANTENNAGATEAREA 0.159000 ;
    PORT
      LAYER met2 ;
        RECT 131.190 488.560 131.470 492.560 ;
    END
  END input_data[60]
  PIN input_data[61]
    DIRECTION INPUT ;
    USE SIGNAL ;
    ANTENNAGATEAREA 0.159000 ;
    PORT
      LAYER met2 ;
        RECT 133.030 488.560 133.310 492.560 ;
    END
  END input_data[61]
  PIN input_data[62]
    DIRECTION INPUT ;
    USE SIGNAL ;
    ANTENNAGATEAREA 0.159000 ;
    PORT
      LAYER met2 ;
        RECT 134.870 488.560 135.150 492.560 ;
    END
  END input_data[62]
  PIN input_data[63]
    DIRECTION INPUT ;
    USE SIGNAL ;
    PORT
      LAYER met2 ;
        RECT 136.710 488.560 136.990 492.560 ;
    END
  END input_data[63]
  PIN input_data[64]
    DIRECTION INPUT ;
    USE SIGNAL ;
    ANTENNAGATEAREA 0.196500 ;
    PORT
      LAYER met2 ;
        RECT 138.550 488.560 138.830 492.560 ;
    END
  END input_data[64]
  PIN input_data[65]
    DIRECTION INPUT ;
    USE SIGNAL ;
    ANTENNAGATEAREA 0.196500 ;
    PORT
      LAYER met2 ;
        RECT 140.390 488.560 140.670 492.560 ;
    END
  END input_data[65]
  PIN input_data[66]
    DIRECTION INPUT ;
    USE SIGNAL ;
    ANTENNAGATEAREA 0.196500 ;
    PORT
      LAYER met2 ;
        RECT 142.230 488.560 142.510 492.560 ;
    END
  END input_data[66]
  PIN input_data[67]
    DIRECTION INPUT ;
    USE SIGNAL ;
    ANTENNAGATEAREA 0.196500 ;
    PORT
      LAYER met2 ;
        RECT 144.070 488.560 144.350 492.560 ;
    END
  END input_data[67]
  PIN input_data[68]
    DIRECTION INPUT ;
    USE SIGNAL ;
    ANTENNAGATEAREA 0.159000 ;
    PORT
      LAYER met2 ;
        RECT 145.910 488.560 146.190 492.560 ;
    END
  END input_data[68]
  PIN input_data[69]
    DIRECTION INPUT ;
    USE SIGNAL ;
    ANTENNAGATEAREA 0.126000 ;
    PORT
      LAYER met2 ;
        RECT 147.750 488.560 148.030 492.560 ;
    END
  END input_data[69]
  PIN input_data[6]
    DIRECTION INPUT ;
    USE SIGNAL ;
    ANTENNAGATEAREA 0.159000 ;
    PORT
      LAYER met2 ;
        RECT 31.830 488.560 32.110 492.560 ;
    END
  END input_data[6]
  PIN input_data[70]
    DIRECTION INPUT ;
    USE SIGNAL ;
    ANTENNAGATEAREA 0.126000 ;
    PORT
      LAYER met2 ;
        RECT 149.590 488.560 149.870 492.560 ;
    END
  END input_data[70]
  PIN input_data[71]
    DIRECTION INPUT ;
    USE SIGNAL ;
    ANTENNAGATEAREA 0.213000 ;
    PORT
      LAYER met2 ;
        RECT 151.430 488.560 151.710 492.560 ;
    END
  END input_data[71]
  PIN input_data[72]
    DIRECTION INPUT ;
    USE SIGNAL ;
    ANTENNAGATEAREA 0.196500 ;
    PORT
      LAYER met2 ;
        RECT 153.270 488.560 153.550 492.560 ;
    END
  END input_data[72]
  PIN input_data[73]
    DIRECTION INPUT ;
    USE SIGNAL ;
    ANTENNAGATEAREA 0.213000 ;
    PORT
      LAYER met2 ;
        RECT 155.110 488.560 155.390 492.560 ;
    END
  END input_data[73]
  PIN input_data[74]
    DIRECTION INPUT ;
    USE SIGNAL ;
    ANTENNAGATEAREA 0.213000 ;
    PORT
      LAYER met2 ;
        RECT 156.950 488.560 157.230 492.560 ;
    END
  END input_data[74]
  PIN input_data[75]
    DIRECTION INPUT ;
    USE SIGNAL ;
    ANTENNAGATEAREA 0.196500 ;
    PORT
      LAYER met2 ;
        RECT 158.790 488.560 159.070 492.560 ;
    END
  END input_data[75]
  PIN input_data[76]
    DIRECTION INPUT ;
    USE SIGNAL ;
    ANTENNAGATEAREA 0.196500 ;
    PORT
      LAYER met2 ;
        RECT 160.630 488.560 160.910 492.560 ;
    END
  END input_data[76]
  PIN input_data[77]
    DIRECTION INPUT ;
    USE SIGNAL ;
    ANTENNAGATEAREA 0.213000 ;
    PORT
      LAYER met2 ;
        RECT 162.470 488.560 162.750 492.560 ;
    END
  END input_data[77]
  PIN input_data[78]
    DIRECTION INPUT ;
    USE SIGNAL ;
    ANTENNAGATEAREA 0.196500 ;
    PORT
      LAYER met2 ;
        RECT 164.310 488.560 164.590 492.560 ;
    END
  END input_data[78]
  PIN input_data[79]
    DIRECTION INPUT ;
    USE SIGNAL ;
    PORT
      LAYER met2 ;
        RECT 166.150 488.560 166.430 492.560 ;
    END
  END input_data[79]
  PIN input_data[7]
    DIRECTION INPUT ;
    USE SIGNAL ;
    ANTENNAGATEAREA 0.213000 ;
    PORT
      LAYER met2 ;
        RECT 33.670 488.560 33.950 492.560 ;
    END
  END input_data[7]
  PIN input_data[80]
    DIRECTION INPUT ;
    USE SIGNAL ;
    ANTENNAGATEAREA 0.159000 ;
    PORT
      LAYER met2 ;
        RECT 167.990 488.560 168.270 492.560 ;
    END
  END input_data[80]
  PIN input_data[81]
    DIRECTION INPUT ;
    USE SIGNAL ;
    ANTENNAGATEAREA 0.159000 ;
    PORT
      LAYER met2 ;
        RECT 169.830 488.560 170.110 492.560 ;
    END
  END input_data[81]
  PIN input_data[82]
    DIRECTION INPUT ;
    USE SIGNAL ;
    ANTENNAGATEAREA 0.159000 ;
    PORT
      LAYER met2 ;
        RECT 171.670 488.560 171.950 492.560 ;
    END
  END input_data[82]
  PIN input_data[83]
    DIRECTION INPUT ;
    USE SIGNAL ;
    ANTENNAGATEAREA 0.213000 ;
    PORT
      LAYER met2 ;
        RECT 173.510 488.560 173.790 492.560 ;
    END
  END input_data[83]
  PIN input_data[84]
    DIRECTION INPUT ;
    USE SIGNAL ;
    ANTENNAGATEAREA 0.213000 ;
    PORT
      LAYER met2 ;
        RECT 175.350 488.560 175.630 492.560 ;
    END
  END input_data[84]
  PIN input_data[85]
    DIRECTION INPUT ;
    USE SIGNAL ;
    ANTENNAGATEAREA 0.213000 ;
    PORT
      LAYER met2 ;
        RECT 177.190 488.560 177.470 492.560 ;
    END
  END input_data[85]
  PIN input_data[86]
    DIRECTION INPUT ;
    USE SIGNAL ;
    ANTENNAGATEAREA 0.213000 ;
    PORT
      LAYER met2 ;
        RECT 179.030 488.560 179.310 492.560 ;
    END
  END input_data[86]
  PIN input_data[87]
    DIRECTION INPUT ;
    USE SIGNAL ;
    ANTENNAGATEAREA 0.159000 ;
    PORT
      LAYER met2 ;
        RECT 180.870 488.560 181.150 492.560 ;
    END
  END input_data[87]
  PIN input_data[88]
    DIRECTION INPUT ;
    USE SIGNAL ;
    ANTENNAGATEAREA 0.213000 ;
    PORT
      LAYER met2 ;
        RECT 182.710 488.560 182.990 492.560 ;
    END
  END input_data[88]
  PIN input_data[89]
    DIRECTION INPUT ;
    USE SIGNAL ;
    ANTENNAGATEAREA 0.247500 ;
    PORT
      LAYER met2 ;
        RECT 184.550 488.560 184.830 492.560 ;
    END
  END input_data[89]
  PIN input_data[8]
    DIRECTION INPUT ;
    USE SIGNAL ;
    ANTENNAGATEAREA 0.159000 ;
    PORT
      LAYER met2 ;
        RECT 35.510 488.560 35.790 492.560 ;
    END
  END input_data[8]
  PIN input_data[90]
    DIRECTION INPUT ;
    USE SIGNAL ;
    ANTENNAGATEAREA 0.159000 ;
    PORT
      LAYER met2 ;
        RECT 186.390 488.560 186.670 492.560 ;
    END
  END input_data[90]
  PIN input_data[91]
    DIRECTION INPUT ;
    USE SIGNAL ;
    ANTENNAGATEAREA 0.213000 ;
    PORT
      LAYER met2 ;
        RECT 188.230 488.560 188.510 492.560 ;
    END
  END input_data[91]
  PIN input_data[92]
    DIRECTION INPUT ;
    USE SIGNAL ;
    ANTENNAGATEAREA 0.213000 ;
    PORT
      LAYER met2 ;
        RECT 190.070 488.560 190.350 492.560 ;
    END
  END input_data[92]
  PIN input_data[93]
    DIRECTION INPUT ;
    USE SIGNAL ;
    ANTENNAGATEAREA 0.247500 ;
    PORT
      LAYER met2 ;
        RECT 191.910 488.560 192.190 492.560 ;
    END
  END input_data[93]
  PIN input_data[94]
    DIRECTION INPUT ;
    USE SIGNAL ;
    ANTENNAGATEAREA 0.213000 ;
    PORT
      LAYER met2 ;
        RECT 193.750 488.560 194.030 492.560 ;
    END
  END input_data[94]
  PIN input_data[95]
    DIRECTION INPUT ;
    USE SIGNAL ;
    ANTENNAGATEAREA 0.126000 ;
    PORT
      LAYER met2 ;
        RECT 195.590 488.560 195.870 492.560 ;
    END
  END input_data[95]
  PIN input_data[96]
    DIRECTION INPUT ;
    USE SIGNAL ;
    ANTENNAGATEAREA 0.213000 ;
    PORT
      LAYER met2 ;
        RECT 197.430 488.560 197.710 492.560 ;
    END
  END input_data[96]
  PIN input_data[97]
    DIRECTION INPUT ;
    USE SIGNAL ;
    ANTENNAGATEAREA 0.159000 ;
    PORT
      LAYER met2 ;
        RECT 199.270 488.560 199.550 492.560 ;
    END
  END input_data[97]
  PIN input_data[98]
    DIRECTION INPUT ;
    USE SIGNAL ;
    ANTENNAGATEAREA 0.196500 ;
    PORT
      LAYER met2 ;
        RECT 201.110 488.560 201.390 492.560 ;
    END
  END input_data[98]
  PIN input_data[99]
    DIRECTION INPUT ;
    USE SIGNAL ;
    ANTENNAGATEAREA 0.196500 ;
    PORT
      LAYER met2 ;
        RECT 202.950 488.560 203.230 492.560 ;
    END
  END input_data[99]
  PIN input_data[9]
    DIRECTION INPUT ;
    USE SIGNAL ;
    ANTENNAGATEAREA 0.159000 ;
    PORT
      LAYER met2 ;
        RECT 37.350 488.560 37.630 492.560 ;
    END
  END input_data[9]
  PIN output_high[0]
    DIRECTION OUTPUT ;
    USE SIGNAL ;
    ANTENNADIFFAREA 0.445500 ;
    PORT
      LAYER met3 ;
        RECT 0.000 20.440 4.000 21.040 ;
    END
  END output_high[0]
  PIN output_high[10]
    DIRECTION OUTPUT ;
    USE SIGNAL ;
    ANTENNADIFFAREA 0.445500 ;
    PORT
      LAYER met3 ;
        RECT 0.000 319.640 4.000 320.240 ;
    END
  END output_high[10]
  PIN output_high[11]
    DIRECTION OUTPUT ;
    USE SIGNAL ;
    ANTENNADIFFAREA 0.445500 ;
    PORT
      LAYER met3 ;
        RECT 0.000 349.560 4.000 350.160 ;
    END
  END output_high[11]
  PIN output_high[12]
    DIRECTION OUTPUT ;
    USE SIGNAL ;
    ANTENNADIFFAREA 0.445500 ;
    PORT
      LAYER met3 ;
        RECT 0.000 379.480 4.000 380.080 ;
    END
  END output_high[12]
  PIN output_high[13]
    DIRECTION OUTPUT ;
    USE SIGNAL ;
    ANTENNADIFFAREA 0.445500 ;
    PORT
      LAYER met3 ;
        RECT 0.000 409.400 4.000 410.000 ;
    END
  END output_high[13]
  PIN output_high[14]
    DIRECTION OUTPUT ;
    USE SIGNAL ;
    ANTENNADIFFAREA 0.445500 ;
    PORT
      LAYER met3 ;
        RECT 0.000 439.320 4.000 439.920 ;
    END
  END output_high[14]
  PIN output_high[15]
    DIRECTION OUTPUT ;
    USE SIGNAL ;
    ANTENNADIFFAREA 0.445500 ;
    PORT
      LAYER met3 ;
        RECT 0.000 469.240 4.000 469.840 ;
    END
  END output_high[15]
  PIN output_high[1]
    DIRECTION OUTPUT ;
    USE SIGNAL ;
    ANTENNADIFFAREA 0.445500 ;
    PORT
      LAYER met3 ;
        RECT 0.000 50.360 4.000 50.960 ;
    END
  END output_high[1]
  PIN output_high[2]
    DIRECTION OUTPUT ;
    USE SIGNAL ;
    ANTENNADIFFAREA 0.445500 ;
    PORT
      LAYER met3 ;
        RECT 0.000 80.280 4.000 80.880 ;
    END
  END output_high[2]
  PIN output_high[3]
    DIRECTION OUTPUT ;
    USE SIGNAL ;
    ANTENNADIFFAREA 0.445500 ;
    PORT
      LAYER met3 ;
        RECT 0.000 110.200 4.000 110.800 ;
    END
  END output_high[3]
  PIN output_high[4]
    DIRECTION OUTPUT ;
    USE SIGNAL ;
    ANTENNADIFFAREA 0.445500 ;
    PORT
      LAYER met3 ;
        RECT 0.000 140.120 4.000 140.720 ;
    END
  END output_high[4]
  PIN output_high[5]
    DIRECTION OUTPUT ;
    USE SIGNAL ;
    ANTENNADIFFAREA 0.445500 ;
    PORT
      LAYER met3 ;
        RECT 0.000 170.040 4.000 170.640 ;
    END
  END output_high[5]
  PIN output_high[6]
    DIRECTION OUTPUT ;
    USE SIGNAL ;
    ANTENNADIFFAREA 0.445500 ;
    PORT
      LAYER met3 ;
        RECT 0.000 199.960 4.000 200.560 ;
    END
  END output_high[6]
  PIN output_high[7]
    DIRECTION OUTPUT ;
    USE SIGNAL ;
    ANTENNADIFFAREA 0.445500 ;
    PORT
      LAYER met3 ;
        RECT 0.000 229.880 4.000 230.480 ;
    END
  END output_high[7]
  PIN output_high[8]
    DIRECTION OUTPUT ;
    USE SIGNAL ;
    ANTENNADIFFAREA 0.445500 ;
    PORT
      LAYER met3 ;
        RECT 0.000 259.800 4.000 260.400 ;
    END
  END output_high[8]
  PIN output_high[9]
    DIRECTION OUTPUT ;
    USE SIGNAL ;
    ANTENNADIFFAREA 0.445500 ;
    PORT
      LAYER met3 ;
        RECT 0.000 289.720 4.000 290.320 ;
    END
  END output_high[9]
  PIN tap[0]
    DIRECTION INPUT ;
    USE SIGNAL ;
    ANTENNAGATEAREA 0.213000 ;
    PORT
      LAYER met2 ;
        RECT 60.350 0.000 60.630 4.000 ;
    END
  END tap[0]
  PIN tap[1]
    DIRECTION INPUT ;
    USE SIGNAL ;
    ANTENNAGATEAREA 0.213000 ;
    PORT
      LAYER met2 ;
        RECT 180.410 0.000 180.690 4.000 ;
    END
  END tap[1]
  PIN tap[2]
    DIRECTION INPUT ;
    USE SIGNAL ;
    ANTENNAGATEAREA 0.247500 ;
    PORT
      LAYER met2 ;
        RECT 300.470 0.000 300.750 4.000 ;
    END
  END tap[2]
  PIN tap[3]
    DIRECTION INPUT ;
    USE SIGNAL ;
    ANTENNAGATEAREA 0.247500 ;
    PORT
      LAYER met2 ;
        RECT 420.530 0.000 420.810 4.000 ;
    END
  END tap[3]
  OBS
      LAYER li1 ;
        RECT 5.520 10.795 476.100 481.525 ;
      LAYER met1 ;
        RECT 3.750 10.640 476.100 483.100 ;
      LAYER met2 ;
        RECT 3.770 488.280 20.510 489.330 ;
        RECT 21.350 488.280 22.350 489.330 ;
        RECT 23.190 488.280 24.190 489.330 ;
        RECT 25.030 488.280 26.030 489.330 ;
        RECT 26.870 488.280 27.870 489.330 ;
        RECT 28.710 488.280 29.710 489.330 ;
        RECT 30.550 488.280 31.550 489.330 ;
        RECT 32.390 488.280 33.390 489.330 ;
        RECT 34.230 488.280 35.230 489.330 ;
        RECT 36.070 488.280 37.070 489.330 ;
        RECT 37.910 488.280 38.910 489.330 ;
        RECT 39.750 488.280 40.750 489.330 ;
        RECT 41.590 488.280 42.590 489.330 ;
        RECT 43.430 488.280 44.430 489.330 ;
        RECT 45.270 488.280 46.270 489.330 ;
        RECT 47.110 488.280 48.110 489.330 ;
        RECT 48.950 488.280 49.950 489.330 ;
        RECT 50.790 488.280 51.790 489.330 ;
        RECT 52.630 488.280 53.630 489.330 ;
        RECT 54.470 488.280 55.470 489.330 ;
        RECT 56.310 488.280 57.310 489.330 ;
        RECT 58.150 488.280 59.150 489.330 ;
        RECT 59.990 488.280 60.990 489.330 ;
        RECT 61.830 488.280 62.830 489.330 ;
        RECT 63.670 488.280 64.670 489.330 ;
        RECT 65.510 488.280 66.510 489.330 ;
        RECT 67.350 488.280 68.350 489.330 ;
        RECT 69.190 488.280 70.190 489.330 ;
        RECT 71.030 488.280 72.030 489.330 ;
        RECT 72.870 488.280 73.870 489.330 ;
        RECT 74.710 488.280 75.710 489.330 ;
        RECT 76.550 488.280 77.550 489.330 ;
        RECT 78.390 488.280 79.390 489.330 ;
        RECT 80.230 488.280 81.230 489.330 ;
        RECT 82.070 488.280 83.070 489.330 ;
        RECT 83.910 488.280 84.910 489.330 ;
        RECT 85.750 488.280 86.750 489.330 ;
        RECT 87.590 488.280 88.590 489.330 ;
        RECT 89.430 488.280 90.430 489.330 ;
        RECT 91.270 488.280 92.270 489.330 ;
        RECT 93.110 488.280 94.110 489.330 ;
        RECT 94.950 488.280 95.950 489.330 ;
        RECT 96.790 488.280 97.790 489.330 ;
        RECT 98.630 488.280 99.630 489.330 ;
        RECT 100.470 488.280 101.470 489.330 ;
        RECT 102.310 488.280 103.310 489.330 ;
        RECT 104.150 488.280 105.150 489.330 ;
        RECT 105.990 488.280 106.990 489.330 ;
        RECT 107.830 488.280 108.830 489.330 ;
        RECT 109.670 488.280 110.670 489.330 ;
        RECT 111.510 488.280 112.510 489.330 ;
        RECT 113.350 488.280 114.350 489.330 ;
        RECT 115.190 488.280 116.190 489.330 ;
        RECT 117.030 488.280 118.030 489.330 ;
        RECT 118.870 488.280 119.870 489.330 ;
        RECT 120.710 488.280 121.710 489.330 ;
        RECT 122.550 488.280 123.550 489.330 ;
        RECT 124.390 488.280 125.390 489.330 ;
        RECT 126.230 488.280 127.230 489.330 ;
        RECT 128.070 488.280 129.070 489.330 ;
        RECT 129.910 488.280 130.910 489.330 ;
        RECT 131.750 488.280 132.750 489.330 ;
        RECT 133.590 488.280 134.590 489.330 ;
        RECT 135.430 488.280 136.430 489.330 ;
        RECT 137.270 488.280 138.270 489.330 ;
        RECT 139.110 488.280 140.110 489.330 ;
        RECT 140.950 488.280 141.950 489.330 ;
        RECT 142.790 488.280 143.790 489.330 ;
        RECT 144.630 488.280 145.630 489.330 ;
        RECT 146.470 488.280 147.470 489.330 ;
        RECT 148.310 488.280 149.310 489.330 ;
        RECT 150.150 488.280 151.150 489.330 ;
        RECT 151.990 488.280 152.990 489.330 ;
        RECT 153.830 488.280 154.830 489.330 ;
        RECT 155.670 488.280 156.670 489.330 ;
        RECT 157.510 488.280 158.510 489.330 ;
        RECT 159.350 488.280 160.350 489.330 ;
        RECT 161.190 488.280 162.190 489.330 ;
        RECT 163.030 488.280 164.030 489.330 ;
        RECT 164.870 488.280 165.870 489.330 ;
        RECT 166.710 488.280 167.710 489.330 ;
        RECT 168.550 488.280 169.550 489.330 ;
        RECT 170.390 488.280 171.390 489.330 ;
        RECT 172.230 488.280 173.230 489.330 ;
        RECT 174.070 488.280 175.070 489.330 ;
        RECT 175.910 488.280 176.910 489.330 ;
        RECT 177.750 488.280 178.750 489.330 ;
        RECT 179.590 488.280 180.590 489.330 ;
        RECT 181.430 488.280 182.430 489.330 ;
        RECT 183.270 488.280 184.270 489.330 ;
        RECT 185.110 488.280 186.110 489.330 ;
        RECT 186.950 488.280 187.950 489.330 ;
        RECT 188.790 488.280 189.790 489.330 ;
        RECT 190.630 488.280 191.630 489.330 ;
        RECT 192.470 488.280 193.470 489.330 ;
        RECT 194.310 488.280 195.310 489.330 ;
        RECT 196.150 488.280 197.150 489.330 ;
        RECT 197.990 488.280 198.990 489.330 ;
        RECT 199.830 488.280 200.830 489.330 ;
        RECT 201.670 488.280 202.670 489.330 ;
        RECT 203.510 488.280 204.510 489.330 ;
        RECT 205.350 488.280 206.350 489.330 ;
        RECT 207.190 488.280 208.190 489.330 ;
        RECT 209.030 488.280 210.030 489.330 ;
        RECT 210.870 488.280 211.870 489.330 ;
        RECT 212.710 488.280 213.710 489.330 ;
        RECT 214.550 488.280 215.550 489.330 ;
        RECT 216.390 488.280 217.390 489.330 ;
        RECT 218.230 488.280 219.230 489.330 ;
        RECT 220.070 488.280 221.070 489.330 ;
        RECT 221.910 488.280 222.910 489.330 ;
        RECT 223.750 488.280 224.750 489.330 ;
        RECT 225.590 488.280 226.590 489.330 ;
        RECT 227.430 488.280 228.430 489.330 ;
        RECT 229.270 488.280 230.270 489.330 ;
        RECT 231.110 488.280 232.110 489.330 ;
        RECT 232.950 488.280 233.950 489.330 ;
        RECT 234.790 488.280 235.790 489.330 ;
        RECT 236.630 488.280 237.630 489.330 ;
        RECT 238.470 488.280 239.470 489.330 ;
        RECT 240.310 488.280 241.310 489.330 ;
        RECT 242.150 488.280 243.150 489.330 ;
        RECT 243.990 488.280 244.990 489.330 ;
        RECT 245.830 488.280 246.830 489.330 ;
        RECT 247.670 488.280 248.670 489.330 ;
        RECT 249.510 488.280 250.510 489.330 ;
        RECT 251.350 488.280 252.350 489.330 ;
        RECT 253.190 488.280 254.190 489.330 ;
        RECT 255.030 488.280 256.030 489.330 ;
        RECT 256.870 488.280 257.870 489.330 ;
        RECT 258.710 488.280 259.710 489.330 ;
        RECT 260.550 488.280 261.550 489.330 ;
        RECT 262.390 488.280 263.390 489.330 ;
        RECT 264.230 488.280 265.230 489.330 ;
        RECT 266.070 488.280 267.070 489.330 ;
        RECT 267.910 488.280 268.910 489.330 ;
        RECT 269.750 488.280 270.750 489.330 ;
        RECT 271.590 488.280 272.590 489.330 ;
        RECT 273.430 488.280 274.430 489.330 ;
        RECT 275.270 488.280 276.270 489.330 ;
        RECT 277.110 488.280 278.110 489.330 ;
        RECT 278.950 488.280 279.950 489.330 ;
        RECT 280.790 488.280 281.790 489.330 ;
        RECT 282.630 488.280 283.630 489.330 ;
        RECT 284.470 488.280 285.470 489.330 ;
        RECT 286.310 488.280 287.310 489.330 ;
        RECT 288.150 488.280 289.150 489.330 ;
        RECT 289.990 488.280 290.990 489.330 ;
        RECT 291.830 488.280 292.830 489.330 ;
        RECT 293.670 488.280 294.670 489.330 ;
        RECT 295.510 488.280 296.510 489.330 ;
        RECT 297.350 488.280 298.350 489.330 ;
        RECT 299.190 488.280 300.190 489.330 ;
        RECT 301.030 488.280 302.030 489.330 ;
        RECT 302.870 488.280 303.870 489.330 ;
        RECT 304.710 488.280 305.710 489.330 ;
        RECT 306.550 488.280 307.550 489.330 ;
        RECT 308.390 488.280 309.390 489.330 ;
        RECT 310.230 488.280 311.230 489.330 ;
        RECT 312.070 488.280 313.070 489.330 ;
        RECT 313.910 488.280 314.910 489.330 ;
        RECT 315.750 488.280 316.750 489.330 ;
        RECT 317.590 488.280 318.590 489.330 ;
        RECT 319.430 488.280 320.430 489.330 ;
        RECT 321.270 488.280 322.270 489.330 ;
        RECT 323.110 488.280 324.110 489.330 ;
        RECT 324.950 488.280 325.950 489.330 ;
        RECT 326.790 488.280 327.790 489.330 ;
        RECT 328.630 488.280 329.630 489.330 ;
        RECT 330.470 488.280 331.470 489.330 ;
        RECT 332.310 488.280 333.310 489.330 ;
        RECT 334.150 488.280 335.150 489.330 ;
        RECT 335.990 488.280 336.990 489.330 ;
        RECT 337.830 488.280 338.830 489.330 ;
        RECT 339.670 488.280 340.670 489.330 ;
        RECT 341.510 488.280 342.510 489.330 ;
        RECT 343.350 488.280 344.350 489.330 ;
        RECT 345.190 488.280 346.190 489.330 ;
        RECT 347.030 488.280 348.030 489.330 ;
        RECT 348.870 488.280 349.870 489.330 ;
        RECT 350.710 488.280 351.710 489.330 ;
        RECT 352.550 488.280 353.550 489.330 ;
        RECT 354.390 488.280 355.390 489.330 ;
        RECT 356.230 488.280 357.230 489.330 ;
        RECT 358.070 488.280 359.070 489.330 ;
        RECT 359.910 488.280 360.910 489.330 ;
        RECT 361.750 488.280 362.750 489.330 ;
        RECT 363.590 488.280 364.590 489.330 ;
        RECT 365.430 488.280 366.430 489.330 ;
        RECT 367.270 488.280 368.270 489.330 ;
        RECT 369.110 488.280 370.110 489.330 ;
        RECT 370.950 488.280 371.950 489.330 ;
        RECT 372.790 488.280 373.790 489.330 ;
        RECT 374.630 488.280 375.630 489.330 ;
        RECT 376.470 488.280 377.470 489.330 ;
        RECT 378.310 488.280 379.310 489.330 ;
        RECT 380.150 488.280 381.150 489.330 ;
        RECT 381.990 488.280 382.990 489.330 ;
        RECT 383.830 488.280 384.830 489.330 ;
        RECT 385.670 488.280 386.670 489.330 ;
        RECT 387.510 488.280 388.510 489.330 ;
        RECT 389.350 488.280 390.350 489.330 ;
        RECT 391.190 488.280 392.190 489.330 ;
        RECT 393.030 488.280 394.030 489.330 ;
        RECT 394.870 488.280 395.870 489.330 ;
        RECT 396.710 488.280 397.710 489.330 ;
        RECT 398.550 488.280 399.550 489.330 ;
        RECT 400.390 488.280 401.390 489.330 ;
        RECT 402.230 488.280 403.230 489.330 ;
        RECT 404.070 488.280 405.070 489.330 ;
        RECT 405.910 488.280 406.910 489.330 ;
        RECT 407.750 488.280 408.750 489.330 ;
        RECT 409.590 488.280 410.590 489.330 ;
        RECT 411.430 488.280 412.430 489.330 ;
        RECT 413.270 488.280 414.270 489.330 ;
        RECT 415.110 488.280 416.110 489.330 ;
        RECT 416.950 488.280 417.950 489.330 ;
        RECT 418.790 488.280 419.790 489.330 ;
        RECT 420.630 488.280 421.630 489.330 ;
        RECT 422.470 488.280 423.470 489.330 ;
        RECT 424.310 488.280 425.310 489.330 ;
        RECT 426.150 488.280 427.150 489.330 ;
        RECT 427.990 488.280 428.990 489.330 ;
        RECT 429.830 488.280 430.830 489.330 ;
        RECT 431.670 488.280 432.670 489.330 ;
        RECT 433.510 488.280 434.510 489.330 ;
        RECT 435.350 488.280 436.350 489.330 ;
        RECT 437.190 488.280 438.190 489.330 ;
        RECT 439.030 488.280 440.030 489.330 ;
        RECT 440.870 488.280 441.870 489.330 ;
        RECT 442.710 488.280 443.710 489.330 ;
        RECT 444.550 488.280 445.550 489.330 ;
        RECT 446.390 488.280 447.390 489.330 ;
        RECT 448.230 488.280 449.230 489.330 ;
        RECT 450.070 488.280 451.070 489.330 ;
        RECT 451.910 488.280 452.910 489.330 ;
        RECT 453.750 488.280 454.750 489.330 ;
        RECT 455.590 488.280 456.590 489.330 ;
        RECT 457.430 488.280 458.430 489.330 ;
        RECT 459.270 488.280 460.270 489.330 ;
        RECT 461.110 488.280 473.700 489.330 ;
        RECT 3.770 4.280 473.700 488.280 ;
        RECT 3.770 4.000 60.070 4.280 ;
        RECT 60.910 4.000 180.130 4.280 ;
        RECT 180.970 4.000 300.190 4.280 ;
        RECT 301.030 4.000 420.250 4.280 ;
        RECT 421.090 4.000 473.700 4.280 ;
      LAYER met3 ;
        RECT 3.745 470.240 477.840 482.625 ;
        RECT 4.400 468.840 477.840 470.240 ;
        RECT 3.745 440.320 477.840 468.840 ;
        RECT 4.400 438.920 477.840 440.320 ;
        RECT 3.745 410.400 477.840 438.920 ;
        RECT 4.400 409.000 477.840 410.400 ;
        RECT 3.745 380.480 477.840 409.000 ;
        RECT 4.400 379.080 477.840 380.480 ;
        RECT 3.745 350.560 477.840 379.080 ;
        RECT 4.400 349.160 477.840 350.560 ;
        RECT 3.745 320.640 477.840 349.160 ;
        RECT 4.400 319.240 477.840 320.640 ;
        RECT 3.745 290.720 477.840 319.240 ;
        RECT 4.400 289.320 477.840 290.720 ;
        RECT 3.745 260.800 477.840 289.320 ;
        RECT 4.400 259.400 477.840 260.800 ;
        RECT 3.745 245.840 477.840 259.400 ;
        RECT 3.745 244.440 477.440 245.840 ;
        RECT 3.745 230.880 477.840 244.440 ;
        RECT 4.400 229.480 477.840 230.880 ;
        RECT 3.745 200.960 477.840 229.480 ;
        RECT 4.400 199.560 477.840 200.960 ;
        RECT 3.745 171.040 477.840 199.560 ;
        RECT 4.400 169.640 477.840 171.040 ;
        RECT 3.745 141.120 477.840 169.640 ;
        RECT 4.400 139.720 477.840 141.120 ;
        RECT 3.745 111.200 477.840 139.720 ;
        RECT 4.400 109.800 477.840 111.200 ;
        RECT 3.745 81.280 477.840 109.800 ;
        RECT 4.400 79.880 477.840 81.280 ;
        RECT 3.745 51.360 477.840 79.880 ;
        RECT 4.400 49.960 477.840 51.360 ;
        RECT 3.745 21.440 477.840 49.960 ;
        RECT 4.400 20.040 477.840 21.440 ;
        RECT 3.745 10.715 477.840 20.040 ;
      LAYER met4 ;
        RECT 3.975 27.375 20.640 479.225 ;
        RECT 23.040 27.375 23.940 479.225 ;
        RECT 26.340 27.375 174.240 479.225 ;
        RECT 176.640 27.375 177.540 479.225 ;
        RECT 179.940 27.375 327.840 479.225 ;
        RECT 330.240 27.375 331.140 479.225 ;
        RECT 333.540 27.375 449.585 479.225 ;
  END
END highpass
END LIBRARY

